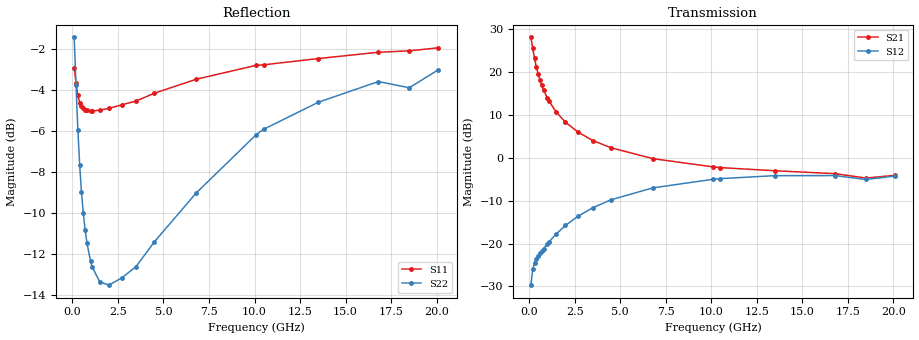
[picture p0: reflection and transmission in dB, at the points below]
!  Infineon Technologies AG
! BFR380L3 , PF131585-7, No.6, Th 09.10.01, soldered on pcb-board, measured with PP GSG850
!  Vce=0.75 V,  Ic=10.0 mA
! Common Emitter S-Parameters:  15. November 2001
#  GHz  S  MA  R  50
! f  S11  S21  S12  S22
! GHz  Mag  Ang  Mag  Ang  Mag  Ang  Mag  Ang
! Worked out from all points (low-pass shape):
!   201 points, 100 MHz to 20.1 GHz, reference 50 ohm
!   highest |S21| = 28.02 dB at 100 MHz (marker M1); lowest = -4.7 dB at 18.5 GHz (marker M2)
!   |S21| within 3 dB of the highest: start of sweep to 221.3 MHz
!   lowest |S11| = -5.0 dB at 1 GHz (marker M3), VSWR 3.54, Z = 14.2 - j3.73 ohm
!   |S11| at or under -10 dB: nowhere
!   |S22| runs from -13.6 to -1.5 dB; largest |S21 - S12| = 25
!   S11 on the Smith chart (normalised r, x): 100 MHz: 0.73, -1.71; 300 MHz: 0.33, -0.58; 1.1 GHz: 0.28, -0.05; 4.5 GHz: 0.29, +0.47; 10.5 GHz: 0.42, +1.23; 20.1 GHz: 0.94, +2.57
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0.1  0.7107 -54.2  25.18 148.1  0.03279 64.7  0.8462 -36.5
0.2  0.6545 -91.7  18.88 127.5  0.05015 51.8  0.6461 -61.4
0.3  0.6116 -115.3  14.41 115.3  0.05964 46.9  0.5044 -77.5
0.4  0.5866 -131.1  11.46 107.2  0.06578 45.3  0.4139 -89.3
0.5  0.5762 -142.0  9.446 101.4  0.07126 45.5  0.3551 -98.5
0.6  0.5689 -150.4  8.01 97.0  0.07658 46.4  0.3152 -106.1
0.7  0.5636 -157.0  6.954 93.3  0.08188 47.4  0.2871 -112.6
0.8  0.5621 -162.2  6.134 90.1  0.08743 48.7  0.2666 -118.2
1  0.5592 -170.7  4.971 84.8  0.09894 50.7  0.2404 -127.6
1.1  0.5596 -174.0  4.543 82.5  0.105 51.5  0.2325 -131.6
1.5  0.5625 174.7  3.386 74.3  0.1299 53.8  0.2145 -144.1
2  0.5676 164.0  2.59 65.6  0.1625 54.4  0.2105 -155.2
2.7  0.5792 151.6  1.979 54.9  0.2087 53.0  0.219 -166.9
3.5  0.592 139.4  1.585 44.1  0.2612 49.6  0.2337 -176.6
4.5  0.6184 126.4  1.305 32.5  0.323 44.1  0.2684 171.4
6.8  0.6689 101.7  0.9748 11.1  0.4453 29.0  0.3532 146.9
10.1  0.7234 76.8  0.7811 -8.7  0.5599 8.0  0.4904 118.7
10.5  0.7254 74.3  0.7664 -10.7  0.5704 5.5  0.505 115.4
13.5  0.7513 59.4  0.7045 -23.9  0.6175 -12.0  0.5878 93.3
16.8  0.7785 47.5  0.6515 -34.9  0.6191 -27.2  0.6603 73.7
18.5  0.7845 45.3  0.5789 -42.2  0.5573 -35.5  0.6378 68.7
20.1  0.7982 38.4  0.6237 -45.7  0.6111 -40.3  0.7057 58.5
